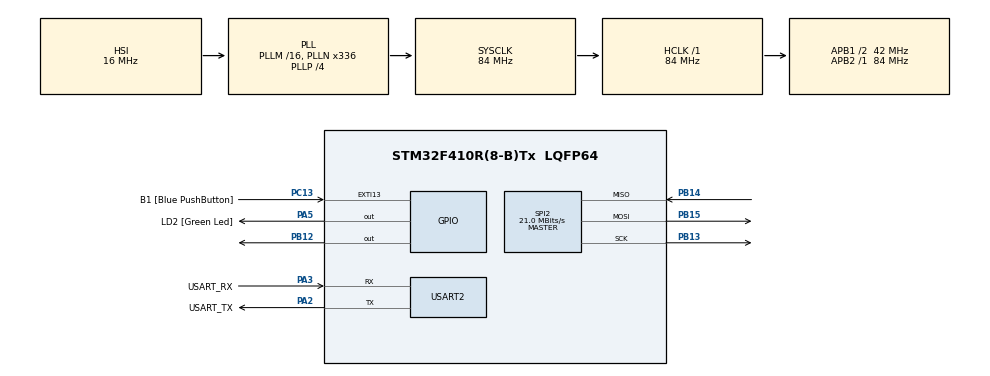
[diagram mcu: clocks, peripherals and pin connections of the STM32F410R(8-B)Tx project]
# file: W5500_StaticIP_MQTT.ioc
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Mcu.Family=STM32F4
Mcu.Name=STM32F410R(8-B)Tx
Mcu.Package=LQFP64
NVIC.PriorityGroup=NVIC_PRIORITYGROUP_0
PA13.GPIO_Label=TMS
PA13.Mode=Serial_Wire
PA13.Signal=SYS_JTMS-SWDIO
PA14.GPIO_Label=TCK
PA14.Mode=Serial_Wire
PA14.Signal=SYS_JTCK-SWCLK
PA2.GPIO_Label=USART_TX
PA2.Mode=Asynchronous
PA2.Signal=USART2_TX
PA3.GPIO_Label=USART_RX
PA3.Mode=Asynchronous
PA3.Signal=USART2_RX
PA5.GPIO_Label=LD2 [Green Led]
PA5.Signal=GPIO_Output
PB12.Signal=GPIO_Output
PB13.Mode=Full_Duplex_Master
PB13.Signal=SPI2_SCK
PB14.Mode=Full_Duplex_Master
PB14.Signal=SPI2_MISO
PB15.Mode=Full_Duplex_Master
PB15.Signal=SPI2_MOSI
PB3.GPIO_Label=SWO
PB3.Signal=SYS_JTDO-SWO
PC13-ANTI_TAMP.GPIO_Label=B1 [Blue PushButton]
PC13-ANTI_TAMP.GPIO_ModeDefaultEXTI=GPIO_MODE_IT_FALLING
PC13-ANTI_TAMP.Signal=GPXTI13
PC14-OSC32_IN.Mode=LSE-External-Oscillator
PC14-OSC32_IN.Signal=RCC_OSC32_IN
PC15-OSC32_OUT.Mode=LSE-External-Oscillator
PC15-OSC32_OUT.Signal=RCC_OSC32_OUT
PH0\ -\ OSC_IN.Mode=HSE-External-Clock-Source
PH0\ -\ OSC_IN.Signal=RCC_OSC_IN
PH1\ -\ OSC_OUT.Mode=HSE-External-Clock-Source
PH1\ -\ OSC_OUT.Signal=RCC_OSC_OUT
ProjectManager.HeapSize=0x200
ProjectManager.StackSize=0x400
ProjectManager.TargetToolchain=STM32CubeIDE
RCC.48MHZClocksFreq_Value=84000000
RCC.AHBFreq_Value=84000000
RCC.APB1CLKDivider=RCC_HCLK_DIV2
RCC.APB1Freq_Value=42000000
RCC.APB1TimFreq_Value=84000000
RCC.APB2Freq_Value=84000000
RCC.APB2TimFreq_Value=84000000
RCC.CortexFreq_Value=84000000
RCC.FLatency-AdvancedSettings=FLASH_LATENCY_2
RCC.HCLKFreq_Value=84000000
RCC.HSE_VALUE=8000000
RCC.HSI_VALUE=16000000
RCC.PLLN=336
RCC.PLLP=RCC_PLLP_DIV4
RCC.SYSCLKFreq_VALUE=84000000
RCC.SYSCLKSource=RCC_SYSCLKSOURCE_PLLCLK
RCC.VCOOutputFreq_Value=336000000
SPI2.CalculateBaudRate=21.0 MBits/s
SPI2.Direction=SPI_DIRECTION_2LINES
SPI2.Mode=SPI_MODE_MASTER
SPI2.VirtualType=VM_MASTER
USART2.VirtualMode=VM_ASYNC
board=NUCLEO-F410RB

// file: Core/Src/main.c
/* USER CODE BEGIN Header */
/**
  ******************************************************************************
  * @file           : main.c
  * @brief          : Main program body
  ******************************************************************************
  * @attention
  *
  * Copyright (c) 2022 STMicroelectronics.
  * All rights reserved.
  *
  * This software is licensed under terms that can be found in the LICENSE file
  * in the root directory of this software component.
  * If no LICENSE file comes with this software, it is provided AS-IS.
  *
  ******************************************************************************
  */
/* USER CODE END Header */

#include "main.h"

/* USER CODE BEGIN Includes */
#include <stm32f4xx_hal.h>
#include <string.h>
#include <stdio.h>

#include "w5500_interface.h"
#include "mqtt_user.h"
#include "dns.h"
/* USER CODE END Includes */

SPI_HandleTypeDef hspi2;

UART_HandleTypeDef huart2;

void SystemClock_Config(void);
static void MX_GPIO_Init(void);
static void MX_USART2_UART_Init(void);
static void MX_SPI2_Init(void);

int main(void)
{

  /* MCU Configuration--------------------------------------------------------*/

  /* Reset of all peripherals, Initializes the Flash interface and the Systick. */
  HAL_Init();

  /* Configure the system clock */
  SystemClock_Config();

  /* Initialize all configured peripherals */
  MX_GPIO_Init();
  MX_USART2_UART_Init();
  MX_SPI2_Init();
  /* USER CODE BEGIN 2 */

  w5500_interface_setSPIHandle(hspi2);

  w5500_interface_Initialze();
  printf("W5500 IC initialized.\n\r");

  /*Set network informations*/
  w5500_interface_SetNetInfo();

  setMQTTBrokerTargetName((char*)"test.mosquitto.org");
  setMQTTSubTargetName((char*)"topic/twat");
  MQTTInitialze();

  int sub_status = 0;
  sub_status = mqttSubscribe();

  setMQTTPubTargetName((char*)"topic/abc");
  unsigned char PubTopicName[] = "topic/abc";

  /* USER CODE END 2 */

  /* Infinite loop */
  /* USER CODE BEGIN WHILE */
  while (1)
  {
	  mqttYield();
	  MQTT_Message publish_message;
	  unsigned char message12[6] = {1,2,3,4,5,6};

	  publish_message.message.qos = QOS0;
	  publish_message.message.dup = 0;
	  publish_message.message.retained = 0;
	  publish_message.message.id = 5;
	  publish_message.message.payload = &message12;
	  publish_message.message.payloadlen = 6;

	  setMQTTPubData(publish_message.message);
	  MQTTPublishMessage();

	  HAL_Delay(1000);

    /* USER CODE END WHILE */

  }
}

void SystemClock_Config(void)
{
  RCC_OscInitTypeDef RCC_OscInitStruct = {0};
  RCC_ClkInitTypeDef RCC_ClkInitStruct = {0};

  /** Configure the main internal regulator output voltage
  */
  __HAL_RCC_PWR_CLK_ENABLE();
  __HAL_PWR_VOLTAGESCALING_CONFIG(PWR_REGULATOR_VOLTAGE_SCALE1);

  /** Initializes the RCC Oscillators according to the specified parameters
  * in the RCC_OscInitTypeDef structure.
  */
  RCC_OscInitStruct.OscillatorType = RCC_OSCILLATORTYPE_HSI;
  RCC_OscInitStruct.HSIState = RCC_HSI_ON;
  RCC_OscInitStruct.HSICalibrationValue = RCC_HSICALIBRATION_DEFAULT;
  RCC_OscInitStruct.PLL.PLLState = RCC_PLL_ON;
  RCC_OscInitStruct.PLL.PLLSource = RCC_PLLSOURCE_HSI;
  RCC_OscInitStruct.PLL.PLLM = 16;
  RCC_OscInitStruct.PLL.PLLN = 336;
  RCC_OscInitStruct.PLL.PLLP = RCC_PLLP_DIV4;
  RCC_OscInitStruct.PLL.PLLQ = 4;
  RCC_OscInitStruct.PLL.PLLR = 2;
  if (HAL_RCC_OscConfig(&RCC_OscInitStruct) != HAL_OK)
  {
    Error_Handler();
  }

  /** Initializes the CPU, AHB and APB buses clocks
  */
  RCC_ClkInitStruct.ClockType = RCC_CLOCKTYPE_HCLK|RCC_CLOCKTYPE_SYSCLK
                              |RCC_CLOCKTYPE_PCLK1|RCC_CLOCKTYPE_PCLK2;
  RCC_ClkInitStruct.SYSCLKSource = RCC_SYSCLKSOURCE_PLLCLK;
  RCC_ClkInitStruct.AHBCLKDivider = RCC_SYSCLK_DIV1;
  RCC_ClkInitStruct.APB1CLKDivider = RCC_HCLK_DIV2;
  RCC_ClkInitStruct.APB2CLKDivider = RCC_HCLK_DIV1;

  if (HAL_RCC_ClockConfig(&RCC_ClkInitStruct, FLASH_LATENCY_2) != HAL_OK)
  {
    Error_Handler();
  }
}

static void MX_SPI2_Init(void)
{

  /* SPI2 parameter configuration*/
  hspi2.Instance = SPI2;
  hspi2.Init.Mode = SPI_MODE_MASTER;
  hspi2.Init.Direction = SPI_DIRECTION_2LINES;
  hspi2.Init.DataSize = SPI_DATASIZE_8BIT;
  hspi2.Init.CLKPolarity = SPI_POLARITY_LOW;
  hspi2.Init.CLKPhase = SPI_PHASE_1EDGE;
  hspi2.Init.NSS = SPI_NSS_SOFT;
  hspi2.Init.BaudRatePrescaler = SPI_BAUDRATEPRESCALER_2;
  hspi2.Init.FirstBit = SPI_FIRSTBIT_MSB;
  hspi2.Init.TIMode = SPI_TIMODE_DISABLE;
  hspi2.Init.CRCCalculation = SPI_CRCCALCULATION_DISABLE;
  hspi2.Init.CRCPolynomial = 15;
  if (HAL_SPI_Init(&hspi2) != HAL_OK)
  {
    Error_Handler();
  }

}

static void MX_USART2_UART_Init(void)
{

  huart2.Instance = USART2;
  huart2.Init.BaudRate = 115200;
  huart2.Init.WordLength = UART_WORDLENGTH_8B;
  huart2.Init.StopBits = UART_STOPBITS_1;
  huart2.Init.Parity = UART_PARITY_NONE;
  huart2.Init.Mode = UART_MODE_TX_RX;
  huart2.Init.HwFlowCtl = UART_HWCONTROL_NONE;
  huart2.Init.OverSampling = UART_OVERSAMPLING_16;
  if (HAL_UART_Init(&huart2) != HAL_OK)
  {
    Error_Handler();
  }

}

static void MX_GPIO_Init(void)
{
  GPIO_InitTypeDef GPIO_InitStruct = {0};

  /* GPIO Ports Clock Enable */
  __HAL_RCC_GPIOC_CLK_ENABLE();
  __HAL_RCC_GPIOH_CLK_ENABLE();
  __HAL_RCC_GPIOA_CLK_ENABLE();
  __HAL_RCC_GPIOB_CLK_ENABLE();

  /*Configure GPIO pin Output Level */
  HAL_GPIO_WritePin(LD2_GPIO_Port, LD2_Pin, GPIO_PIN_RESET);

  /*Configure GPIO pin Output Level */
  HAL_GPIO_WritePin(GPIOC, GPIO_PIN_4|GPIO_PIN_5, GPIO_PIN_RESET);

  /*Configure GPIO pin Output Level */
  HAL_GPIO_WritePin(GPIOB, GPIO_PIN_12, GPIO_PIN_RESET);

  /*Configure GPIO pin : B1_Pin */
  GPIO_InitStruct.Pin = B1_Pin;
  GPIO_InitStruct.Mode = GPIO_MODE_IT_FALLING;
  GPIO_InitStruct.Pull = GPIO_NOPULL;
  HAL_GPIO_Init(B1_GPIO_Port, &GPIO_InitStruct);

  /*Configure GPIO pin : LD2_Pin */
  GPIO_InitStruct.Pin = LD2_Pin;
  GPIO_InitStruct.Mode = GPIO_MODE_OUTPUT_PP;
  GPIO_InitStruct.Pull = GPIO_NOPULL;
  GPIO_InitStruct.Speed = GPIO_SPEED_FREQ_LOW;
  HAL_GPIO_Init(LD2_GPIO_Port, &GPIO_InitStruct);

  /*Configure GPIO pins : PC4 PC5 */
  GPIO_InitStruct.Pin = GPIO_PIN_4|GPIO_PIN_5;
  GPIO_InitStruct.Mode = GPIO_MODE_OUTPUT_PP;
  GPIO_InitStruct.Pull = GPIO_NOPULL;
  GPIO_InitStruct.Speed = GPIO_SPEED_FREQ_LOW;
  HAL_GPIO_Init(GPIOC, &GPIO_InitStruct);

  /*Configure GPIO pin : PB12 */
  GPIO_InitStruct.Pin = GPIO_PIN_12;
  GPIO_InitStruct.Mode = GPIO_MODE_OUTPUT_PP;
  GPIO_InitStruct.Pull = GPIO_NOPULL;
  GPIO_InitStruct.Speed = GPIO_SPEED_FREQ_LOW;
  HAL_GPIO_Init(GPIOB, &GPIO_InitStruct);

}

void Error_Handler(void)
{
  __disable_irq();
  while (1)
  {
  }
}
